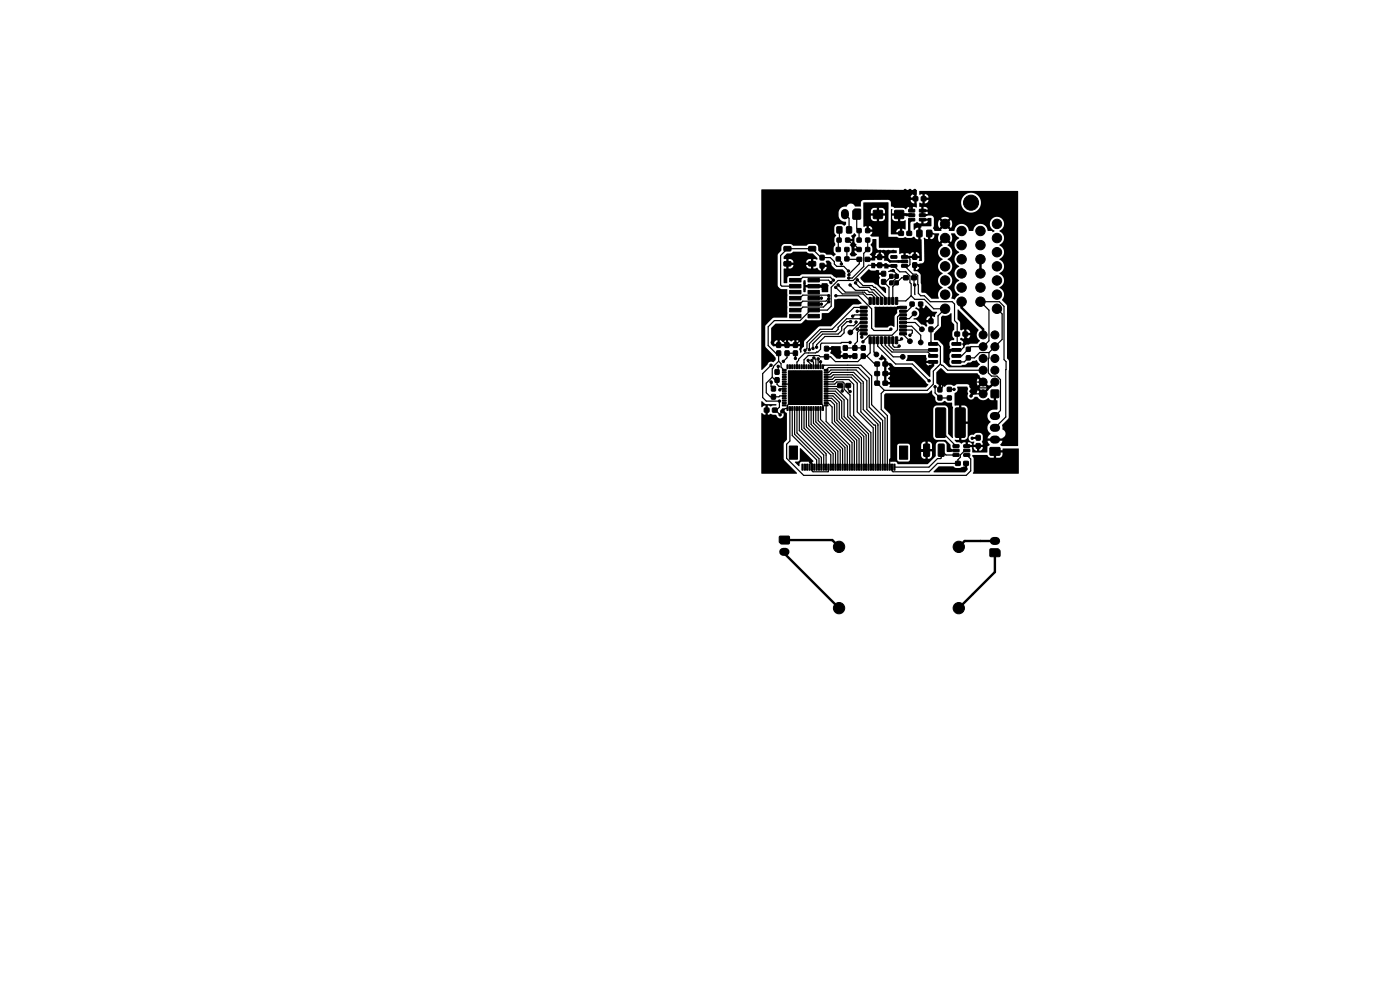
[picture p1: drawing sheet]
<svg xmlns="http://www.w3.org/2000/svg" width="297mm" height="210mm" viewBox="0 0 297 210" stroke-linecap="round" stroke-linejoin="round" font-family="sans-serif">
<g fill="#000" stroke="#000" stroke-width=".21">
<path d="M166.3 55.5h1.4l.1 .2v.6l-.2 .2-1.2-.1-.1-.2zM166.3 52.3h1.4l.1 .2v.6l-.2 .2-1.2-.1-.1-.2zM167.5 59.1h2.4v.7h-2.4zM171.6 55.5h1.3l.2 .2v.6l-.3 .2-1.1-.1-.2-.2zM171.6 52.3h1.3l.2 .2v.6l-.3 .2-1.1-.1-.2-.2zM171.4 59.1h2.4v.7h-2.4zM174 55.9h.8v.9h-.8zM174 54.2h.8v.9h-.8zM177.4 52.5h.9v.8h-.9zM177.6 48.1h1v1.3h-1zM177.6 50.5h.8v.8h-.8zM177.4 54.5h.9v.8h-.9z"/>
<path d="M179.2 52.5h.9v.8h-.9zM179.4 50.5h.8v.8h-.8zM179.6 48.1h1v1.3h-1zM179.2 54.5h.9v.8h-.9zM181.8 50.5h.9v.8h-.9zM181.8 54.6h1v.8h-1zM181 44.7l.4-.4 1.1 .1v2.1h-1.5zM181.8 52.5h.9v.8h-.9zM181.8 48.5h.9v.8h-.9zM183.6 54.6h.9v.8h-.9zM183.7 50.5h.8v.8h-.8zM183.7 52.5h.8v.8h-.8z"/>
<path d="M183.7 48.5h.8v.8h-.8zM186.2 54.1h.8v.9h-.8zM186.2 55.8h.8v.9h-.8zM187 57.6h.9v.9h-.9zM185.3 44.7h1.9v1.6h-1.9zM188.8 58.2h.6v.8h-.6zM188.8 59.6h.6v.8h-.6zM189 54.3l1.2-.1 .1 .5-1.2 .1zM189 56.2l1.2-.1 .1 .5-1.2 .1zM189.9 59.6h.6v.8h-.6zM189.9 58.2h.6v.8h-.6zM190.7 49.1h.9v.8h-.9z"/>
<path d="M191.7 58.5h.9v.8h-.9zM189.8 44.7h1.9v1.6h-1.9zM192.4 49.1h1v.8h-1zM191.3 56.2l1.2-.1 .1 .5-1.3 .1zM191.3 55.2h1.2l.1 .5h-1.3zM191.3 54.3l1.2-.1 .1 .5-1.3 .1zM193.4 58.5h1v.8h-1zM193.7 41.8h1v.8h-1zM193.7 55.8h.8v.9h-.8zM193.7 54h.8v1h-.8zM192.8 44.4h1.2l.1 .5-1.3 .1zM192.8 45.4l1.2-.1 .1 .5-1.3 .1z"/>
<path d="M192.8 46.3h1.2l.1 .5-1.3 .1zM195.5 41.8h.9v.8h-.9zM194.5 48.9h1.1v1.3h-1.1zM195.1 46.3h1.2v.5l-1.2 .1zM195.1 45.4l1.2-.1v.5l-1.2 .1zM195.1 44.4h1.2v.5l-1.2 .1zM196.6 48.9h1v1.3h-1zM164.4 78.4h.9v1h-.9zM164.8 74.5h.8v.9h-.8zM164.8 72.7h.8v1h-.8zM166.6 74.5h.8v.9h-.8zM166.6 72.7h.8v1h-.8z"/>
<path d="M166 78.4h.8v.2h-.8zM166 78.9h.8v.2h-.8zM166 79.4h.8v.2h-.8zM166 79.9h.8v.2h-.8zM167 77.4h.2v.8h-.3zM167.2 78.7h7.2v7.1h-7.2zM167.5 77.4h.2v.8h-.3zM168 77.4h.2v.8h-.3zM168.3 74.5h.8v.9h-.8zM168.3 72.7h.8v1h-.8zM168.5 77.4h.2v.8h-.3zM169 77.4h.2v.8h-.3z"/>
<path d="M169.5 77.4h.2v.8h-.3zM167.5 66.7h2.4v.7h-2.4zM167.5 65.4h2.4v.8h-2.4zM167.5 64.1h2.4v.8h-2.4zM167.5 62.9h2.4v.7h-2.4zM167.5 61.6h2.4v.7h-2.4zM167.5 60.3h2.4v.8h-2.4zM170 77.4h.2v.8h-.3zM170.5 77.4h.2v.8h-.3zM171 77.4h.2v.8h-.3zM171.5 77.4h.2v.8h-.3zM172 77.4h.2v.8h-.3z"/>
<path d="M172.5 77.4h.2v.8h-.3zM173 77.4h.2v.8h-.3zM173.5 77.4h.2v.8h-.3zM171.4 66.7h2.4v.7h-2.4zM171.4 65.4h2.4v.8h-2.4zM171.4 64.1h2.4v.8h-2.4zM171.4 62.9h2.4v.7h-2.4zM171.4 61.6h2.4v.7h-2.4zM171.4 60.3h2.4v.8h-2.4zM174 77.4h.2v.8h-.3zM174.5 77.4h.2v.8h-.3zM174.9 75.2h.9v1h-.9z"/>
<path d="M174.9 73.5h.9v.9h-.9zM174.9 79.9h.7l.1 .2h-.8zM174.9 79.4h.7l.1 .2h-.8zM174.9 78.9h.7l.1 .2h-.8zM174.9 78.4h.7l.1 .2h-.8zM178.9 73.3h.8v1h-.8zM178.9 75.1h.8v.9h-.8zM181 73.3h.8v1h-.8zM181 75.1h.8v.9h-.8zM182.7 75.1h.8v.9h-.8zM182.7 73.3h.8v1h-.8zM182.5 65h1.4l.1 .4h-1.4z"/>
<path d="M182.5 65.8h1.4l.1 .4h-1.4zM182.5 66.6h1.4l.1 .4h-1.4zM182.5 67.4h1.4l.1 .4h-1.4zM182.5 68.2h1.4l.1 .4h-1.4zM182.5 69h1.4l.1 .4h-1.4zM182.5 69.8h1.4l.1 .4h-1.4zM182.5 70.6h1.4l.1 .4h-1.4zM184.4 63.1l.4 .1v1.4l-.4-.1zM184.4 71.5h.4v1.4h-.4zM185.2 63.1l.4 .1v1.4l-.4-.1zM185.2 71.5h.4v1.4h-.4zM186 63.1l.4 .1v1.4l-.4-.1z"/>
<path d="M186 71.5h.4v1.4h-.4zM185.6 78.8h.9v.9h-.9zM185.6 76.8h.9v.8h-.9zM186.8 63.1l.4 .1v1.4l-.4-.1zM186.8 71.5h.4v1.4h-.4zM187 59.3h.9v1h-.9zM187.6 63.1l.4 .1v1.4l-.4-.1zM187.6 71.5h.4v1.4h-.4zM187.3 78.8h1v.9h-1zM187.3 76.8h1v.8h-1zM188.4 63.1l.4 .1v1.4l-.4-.1zM188.4 71.5h.4v1.4h-.4z"/>
<path d="M189.2 63.1l.4 .1v1.4l-.4-.1zM189.2 71.5h.4v1.4h-.4zM190 63.1l.4 .1v1.4l-.4-.1zM190 71.5h.4v1.4h-.4zM190.9 70.6h1.3l.1 .4h-1.4zM190.9 69.8h1.3l.1 .4h-1.4zM190.9 69h1.3l.1 .4h-1.4zM190.9 68.2h1.3l.1 .4h-1.4zM190.9 67.4h1.3l.1 .4h-1.4zM190.9 66.6h1.3l.1 .4h-1.4zM190.9 65.8h1.3l.1 .4h-1.4zM190.9 65h1.3l.1 .4h-1.4z"/>
<path d="M193.1 64.1h.8v.8h-.8zM194.9 64.1h.8v.8h-.8zM197 72.7h1.8l.1 .5h-1.8zM197 74l1.8-.1 .1 .5-1.8 .1zM197 75.2h1.8l.1 .5-1.8 .1zM197 76.5h1.8l.1 .5-1.8 .1zM197.1 69.4h.8v.9h-.8zM197.1 67.7h.8v.9h-.8zM202 76.5h1.8l.1 .5-1.9 .1zM202 75.2h1.8l.1 .5-1.9 .1zM202 74l1.8-.1 .1 .5-1.9 .1zM202 72.7h1.8l.1 .5h-1.9z"/>
<path d="M202.6 70.5h.9v.8h-.9zM204.3 70.5h1v.8h-1zM205 73.7h.8v.8h-.8zM205 75.5h.8v.8h-.8zM162.2 86.6h.9v.8h-.9zM163.7 83.7h.8v.9h-.8zM163.7 82h.8v.9h-.8zM164.4 80.2h.9v.9h-.9zM163.9 86.6h.9v.8h-.9zM166 80.4h.8v.2h-.8zM166 80.9h.8v.2h-.8zM166 81.4h.8v.2h-.8z"/>
<path d="M166 81.9h.8v.2h-.8zM166 82.4h.8v.2h-.8zM166 82.9h.8v.2h-.8zM166 83.4h.8v.2h-.8zM166 83.9h.8v.2h-.8zM166 84.4h.8v.2h-.8zM166 84.9h.8v.2h-.8zM166 85.4h.8v.2h-.8zM166 85.9h.8v.2h-.8zM167 86.3h.2v.8l-.3-.1zM167.5 86.3h.2v.8l-.3-.1zM168 86.3h.2v.8l-.3-.1z"/>
<path d="M168.5 86.3h.2v.8l-.3-.1zM169 86.3h.2v.8l-.3-.1zM167.4 94.6h1.8v2.8h-1.8zM169.5 86.3h.2v.8l-.3-.1zM170 86.3h.2v.8l-.3-.1zM170.1 98.4h.3v1.3h-.3zM170.5 86.3h.2v.8l-.3-.1zM170.6 98.4h.3v1.3h-.3zM171 86.3h.2v.8l-.3-.1zM171.1 98.4h.3v1.3h-.3zM171.5 86.3h.2v.8l-.3-.1zM171.6 98.4h.3v1.3h-.3z"/>
<path d="M172 86.3h.2v.8l-.3-.1zM172.1 98.4h.3v1.3h-.3zM172.5 86.3h.2v.8l-.3-.1zM172.6 98.4h.3v1.3h-.3zM173 86.3h.2v.8l-.3-.1zM173.1 98.4h.3v1.3h-.3zM173.5 86.3h.2v.8l-.3-.1zM173.6 98.4h.3v1.3h-.3zM174 86.3h.2v.8l-.3-.1zM174.1 98.4h.3v1.3h-.3zM174.5 86.3h.2v.8l-.3-.1zM174.6 98.4h.3v1.3h-.3z"/>
<path d="M175.1 98.4h.3v1.3h-.3zM174.9 85.9h.7l.1 .2h-.8zM174.9 85.4h.7l.1 .2h-.8zM174.9 84.9h.7l.1 .2h-.8zM174.9 84.4h.7l.1 .2h-.8zM174.9 83.9h.7l.1 .2h-.8zM174.9 83.4h.7l.1 .2h-.8zM174.9 82.9h.7l.1 .2h-.8zM174.9 82.4h.7l.1 .2h-.8zM174.9 81.9h.7l.1 .2h-.8zM174.9 81.4h.7l.1 .2h-.8zM174.9 80.9h.7l.1 .2h-.8z"/>
<path d="M174.9 80.4h.7l.1 .2h-.8zM175.6 98.4h.3v1.3h-.3zM176.1 98.4h.3v1.3h-.3zM176.6 98.4h.3v1.3h-.3zM177.1 98.4h.3v1.3h-.3zM177.7 81.4h1v.8h-1zM177.6 98.4h.3v1.3h-.3zM178.1 98.4h.3v1.3h-.3zM178.6 98.4h.3v1.3h-.3zM179.1 98.4h.3v1.3h-.3zM179.5 81.4h.9v.8h-.9zM179.6 98.4h.3v1.3h-.3z"/>
<path d="M180.1 98.4h.3v1.3h-.3zM180.6 98.4h.3v1.3h-.3zM181.1 98.4h.3v1.3h-.3zM181.6 98.4h.3v1.3h-.3zM182.1 98.4h.3v1.3h-.3zM182.6 98.4h.3v1.3h-.3zM183.1 98.4h.3v1.3h-.3zM183.6 98.4h.3v1.3h-.3zM184.1 98.4h.3v1.3h-.3zM184.6 98.4h.3v1.3h-.3zM185.1 98.4h.3v1.3h-.3zM185.6 98.4h.3v1.3h-.3z"/>
<path d="M186.1 98.4h.3v1.3h-.3zM185.6 80.9h.9v.8h-.9zM186.6 98.4h.3v1.3h-.3zM187.1 98.4h.3v1.3h-.3zM187.6 98.4h.3v1.3h-.3zM187.3 80.9h1v.8h-1zM188.1 98.4h.3v1.3h-.3zM188.6 98.4h.3v1.3h-.3zM189.1 98.4h.3v1.3h-.3zM189.6 98.4h.3v1.3h-.3zM190.8 94.6h1.8v2.8h-1.8zM196 94.3l1-.1 .2 .1v2.3l-.1 .2h-.9l-.3-.1z"/>
<path d="M198.5 86.6l.3-.1h1.5l.3 .3v5.7l-.2 .3h-1.6l-.3-.2zM199 83.9h.8v.9h-.8zM199 82.2h.8v.9h-.8zM199.1 94.3l1-.1 .2 .1v2.3l-.1 .2h-.9l-.3-.1zM201 82.2h.8v.8h-.8zM201 84h.8v.8h-.8zM202.2 94.4l1.2-.1 .1 .5-1.3 .1zM202.2 95.3h1.2l.1 .5-1.3 .1zM202.2 96.3l1.2-.1 .1 .5-1.3 .1zM202.7 86.6l.3-.1h1.5l.3 .3v5.7l-.3 .3h-1.5l-.4-.2zM202.7 97.9h1v.8h-1zM204.5 97.9h.9v.8h-.9z"/>
<path d="M204.5 96.3l1.2-.1v.5l-1.2 .1zM204.5 95.3h1.2v.5l-1.2 .1zM204.5 94.4l1.2-.1v.5l-1.2 .1zM207.1 94.1h.8v1h-.8zM207.1 92.4h.8v.9h-.8zM210.3 82.8h1.5v1.5h-1.5zM210 95h2.1v1.5h-2.1zM165.4 113.8h2v1.5h-1.8l-.3-.4zM210 116.5h1.8l.4 .4-.1 1.1h-2.1z"/>
<circle cx="172.2" cy="57.4" r=".25"/>
<circle cx="175.8" cy="56.6" r=".25"/>
<circle cx="176.3" cy="59.9" r=".25"/>
<circle cx="176.8" cy="59.4" r=".25"/>
<circle cx="178.5" cy="56" r=".25"/>
<circle cx="180" cy="57.5" r=".25"/>
<circle cx="180.1" cy="59" r=".25"/>
<circle cx="180.1" cy="58.3" r=".25"/>
<circle cx="181" cy="52" r=".25"/>
<circle cx="181.5" cy="60" r=".25"/>
<circle cx="181.9" cy="59.4" r=".25"/>
<circle cx="185.2" cy="54.9" r=".25"/>
<circle cx="185.4" cy="53.8" r=".25"/>
<circle cx="185.9" cy="58.4" r=".25"/>
<circle cx="185.9" cy="53.3" r=".25"/>
<circle cx="186.7" cy="53.3" r=".25"/>
<circle cx="187.5" cy="53.3" r=".25"/>
<circle cx="188" cy="54.6" r=".25"/>
<circle cx="188" cy="53.8" r=".25"/>
<circle cx="188.5" cy="53.3" r=".25"/>
<circle cx="189.5" cy="53.3" r=".25"/>
<circle cx="189.5" cy="57.4" r=".25"/>
<circle cx="191" cy="42.2" r=".25"/>
<circle cx="191" cy="41.1" r=".25"/>
<circle cx="192" cy="42.2" r=".25"/>
<circle cx="192" cy="41.1" r=".25"/>
<circle cx="192" cy="40.4" r=".25"/>
<circle cx="193" cy="43.7" r=".25"/>
<circle cx="193" cy="40.4" r=".25"/>
<circle cx="193" cy="41.1" r=".25"/>
<circle cx="193" cy="42.2" r=".25"/>
<circle cx="194.1" cy="41.1" r=".25"/>
<circle cx="194.1" cy="40.4" r=".25"/>
<circle cx="195.1" cy="56.4" r=".25"/>
<circle cx="195.1" cy="57.4" r=".25"/>
<circle cx="196.1" cy="58.4" r=".25"/>
<circle cx="196.1" cy="56.4" r=".25"/>
<circle cx="196.1" cy="57.4" r=".25"/>
<circle cx="196.6" cy="52.6" r=".25"/>
<circle cx="196.6" cy="51.1" r=".25"/>
<circle cx="196.6" cy="51.8" r=".25"/>
<circle cx="197.1" cy="56.4" r=".25"/>
<circle cx="197.1" cy="57.4" r=".25"/>
<circle cx="197.1" cy="58.4" r=".25"/>
<circle cx="197.4" cy="51.8" r=".25"/>
<circle cx="197.4" cy="52.6" r=".25"/>
<circle cx="197.4" cy="51.1" r=".25"/>
<circle cx="198.1" cy="52.6" r=".25"/>
<circle cx="198.1" cy="56.4" r=".25"/>
<circle cx="198.1" cy="58.4" r=".25"/>
<circle cx="198.1" cy="51.8" r=".25"/>
<circle cx="198.1" cy="51.1" r=".25"/>
<circle cx="198.1" cy="57.4" r=".25"/>
<circle cx="199.4" cy="51.8" r=".25"/>
<circle cx="200.5" cy="53.5" r="1"/>
<circle cx="200.5" cy="59.5" r="1"/>
<circle cx="200.5" cy="50.5" r="1"/>
<circle cx="200.5" cy="56.5" r="1"/>
<circle cx="200.5" cy="47.5" r="1"/>
<circle cx="204" cy="55" r="1"/>
<circle cx="204" cy="49" r="1"/>
<circle cx="204" cy="52" r="1"/>
<circle cx="204" cy="58" r="1"/>
<circle cx="206" cy="43" r="1.6"/>
<circle cx="208" cy="49" r="1"/>
<circle cx="208" cy="55" r="1"/>
<circle cx="208" cy="52" r="1"/>
<circle cx="208" cy="58" r="1"/>
<circle cx="211.5" cy="59.5" r="1"/>
<circle cx="211.5" cy="53.5" r="1"/>
<circle cx="211.5" cy="50.5" r="1"/>
<circle cx="211.5" cy="56.5" r="1"/>
<circle cx="211.5" cy="47.5" r="1"/>
<circle cx="163.6" cy="77.5" r=".25"/>
<circle cx="163.8" cy="72.6" r=".25"/>
<circle cx="165.1" cy="77.7" r=".25"/>
<circle cx="166.1" cy="72.1" r=".25"/>
<circle cx="166.2" cy="76.7" r=".25"/>
<circle cx="168.7" cy="76" r=".25"/>
<circle cx="169.7" cy="71.9" r=".25"/>
<circle cx="170.8" cy="74.3" r=".25"/>
<circle cx="171.4" cy="76.5" r=".25"/>
<circle cx="171.7" cy="74.2" r=".25"/>
<circle cx="172.2" cy="76.5" r=".25"/>
<circle cx="172.5" cy="73.9" r=".25"/>
<circle cx="172.7" cy="75.9" r=".25"/>
<circle cx="173.2" cy="73.7" r=".25"/>
<circle cx="173.6" cy="76.1" r=".25"/>
<circle cx="174.1" cy="76.7" r=".25"/>
<circle cx="174.2" cy="64.5" r=".25"/>
<circle cx="174.2" cy="60.7" r=".25"/>
<circle cx="174.2" cy="63.2" r=".25"/>
<circle cx="175.8" cy="64" r=".25"/>
<circle cx="175.8" cy="63.4" r=".25"/>
<circle cx="175.8" cy="62.7" r=".25"/>
<circle cx="176.6" cy="73.8" r=".25"/>
<circle cx="177.3" cy="61" r=".25"/>
<circle cx="177.3" cy="62.7" r=".25"/>
<circle cx="177.8" cy="60.5" r=".25"/>
<circle cx="178.1" cy="75.7" r=".25"/>
<circle cx="180.3" cy="75.7" r=".25"/>
<circle cx="180.3" cy="72.6" r=".25"/>
<circle cx="180.3" cy="60.5" r=".25"/>
<circle cx="180.4" cy="70.5" r=".5"/>
<circle cx="180.4" cy="68.2" r=".25"/>
<circle cx="180.9" cy="67.1" r=".25"/>
<circle cx="181.6" cy="68.3" r=".25"/>
<circle cx="181.9" cy="69.8" r=".25"/>
<circle cx="181.9" cy="66" r=".25"/>
<circle cx="182.8" cy="71.5" r=".25"/>
<circle cx="183.1" cy="72.5" r=".25"/>
<circle cx="185.9" cy="75.2" r=".5"/>
<circle cx="189" cy="79.2" r=".25"/>
<circle cx="189" cy="77.5" r=".25"/>
<circle cx="189" cy="69.8" r=".25"/>
<circle cx="190.5" cy="65.3" r=".25"/>
<circle cx="190.8" cy="73.4" r=".25"/>
<circle cx="191.3" cy="71.9" r=".25"/>
<circle cx="191.5" cy="75.7" r=".5"/>
<circle cx="193" cy="72.4" r=".5"/>
<circle cx="193" cy="71.1" r=".25"/>
<circle cx="194" cy="66.5" r=".5"/>
<circle cx="194.1" cy="60.5" r=".25"/>
<circle cx="195.3" cy="72.6" r=".5"/>
<circle cx="195.5" cy="65.5" r=".25"/>
<circle cx="195.6" cy="69.9" r=".5"/>
<circle cx="197.4" cy="77.7" r=".25"/>
<circle cx="200.5" cy="62.5" r="1"/>
<circle cx="200.5" cy="65.5" r="1"/>
<circle cx="201.5" cy="74.5" r=".25"/>
<circle cx="204" cy="61" r="1"/>
<circle cx="204" cy="64" r="1"/>
<circle cx="204.5" cy="73" r=".25"/>
<circle cx="205" cy="71.9" r=".25"/>
<circle cx="208" cy="61" r="1"/>
<circle cx="208" cy="64" r="1"/>
<circle cx="208.6" cy="76" r=".85"/>
<circle cx="208.6" cy="73.5" r=".85"/>
<circle cx="208.6" cy="78.5" r=".85"/>
<circle cx="208.6" cy="71" r=".85"/>
<circle cx="211.1" cy="76" r=".85"/>
<circle cx="211.1" cy="73.5" r=".85"/>
<circle cx="211.1" cy="78.5" r=".85"/>
<circle cx="211.1" cy="71" r=".85"/>
<circle cx="211.5" cy="62.5" r="1"/>
<circle cx="211.5" cy="65.5" r="1"/>
<circle cx="163.6" cy="81" r=".25"/>
<circle cx="165.4" cy="85.1" r=".25"/>
<circle cx="165.4" cy="82.7" r=".25"/>
<circle cx="165.5" cy="88" r=".25"/>
<circle cx="165.9" cy="87.4" r=".25"/>
<circle cx="172" cy="98" r=".25"/>
<circle cx="178.7" cy="83" r=".25"/>
<circle cx="180.3" cy="83.1" r=".25"/>
<circle cx="189" cy="97.5" r=".25"/>
<circle cx="189" cy="81.3" r=".25"/>
<circle cx="194.6" cy="95.8" r=".25"/>
<circle cx="197.1" cy="80.8" r=".25"/>
<circle cx="198.4" cy="82" r=".25"/>
<circle cx="200" cy="81.5" r=".25"/>
<circle cx="201.7" cy="95.5" r=".25"/>
<circle cx="202.4" cy="82.6" r=".25"/>
<circle cx="204.5" cy="99.3" r=".25"/>
<circle cx="206" cy="82" r=".25"/>
<circle cx="206" cy="83" r=".25"/>
<circle cx="206" cy="84" r=".25"/>
<circle cx="206.2" cy="93" r=".25"/>
<circle cx="208.6" cy="81" r=".85"/>
<circle cx="208.6" cy="83.5" r=".85"/>
<circle cx="211" cy="98.5" r=".25"/>
<circle cx="211.1" cy="81" r=".85"/>
<circle cx="178" cy="116" r="1.2"/>
<circle cx="203.4" cy="116" r="1.2"/>
<circle cx="178" cy="129" r="1.2"/>
<circle cx="203.4" cy="129" r="1.2"/>
</g>
<path d="M179.2 45.2v.5M210.8 93.3h.5M210.8 90.8h.5M210.8 88.3h.5M166.1 117.1h.5M210.8 114.8h.5" fill="none" stroke="#000" stroke-width="1.7"/>
<g fill="none" stroke="#000" stroke-width=".25">
<path d="M168.7 59.4h1l.6-.6h5.9l.6 .6M172.3 56l-.1 1.4M172.6 59.4h3.2l.5 .5M174.4 56.4h1.1l.3 .2M177.8 54.9l.7 .7v.4M178.1 48.8v2.1l-.3 .2v1.8M179 56.5h-1.5l-.5-.5v-.5l-.9-.9h-1.9l-1.9-1.8h-5.3l-1.4 1.4v6.3l.3 .2h2.8M179 56.5h.1M179 56.5l1 1M179.2 45.4l.9 .9v2.5M179.7 52.9l.1 2.1h2.5v1l-2.2 2.3M179.9 50.9l1.1 1.1h.3l.9 .9"/>
<path d="M181.7 45.4v3l.5 .5v2M181.9 59.4l1.2 1.2h1.9l.4 .4h.3l2.1 2.1v.7M184.1 52.9l-.9 .8v2.8l-2.4 2.5h-.7M184.1 50.9v2h-.2M185.2 54.9l-.2 .1h-1M186.3 45.5v.7M186.6 56.3l.2 .1M187.8 58.1h-1.5l-.4 .3M189.1 58.6l-1.2 1.2h-.4l1.1 1.1v2.9M189.5 57.4l.7 .7v.8l-1.1 1.1M192 54.4l-.1 .1h.7l.4 .5v1.1l-.2 .3h-.9l1.8 1.8h.7l.3 .3 .1 3.7 .5 .5h.8l1.2 1.3h4.7l.5 .5v3.5l.6 .6v4.2l-.2 .2M192.2 58.9h-.9l-1.9 1.9v3"/>
<path d="M193 43.7v.6l.4 .4M193.9 58.9v1.4l.2 .2M200.5 50.5h.1M200.5 50.5v.2l-1.1 1.1M163.6 77.5l-1.8 1.7v5.1l.8 .8h2.8v1.3l-.7 .6h-.3M163.8 72.6l.6 .6h.8M165.1 77.7v.9l-.3 .3M165.2 76.6l.5 .5v.8l.6 .6M165.2 76.6l-1.1 1.1v.3l-.3 .2v1.8M166.1 72.1v.3l.9 .8M168.7 76v-1.1h-1.7v1l-.8 .8M169.7 71.9v.4l-1 .9"/>
<path d="M171.4 76.5v.2l.7 .6v.5M172.2 76.5l.4 .3v1M172.6 60.7h1.6M172.6 63.2h1.6M172.6 64.5h1.6M172.7 75.9l.4 .4v1.5M173.6 76.1v1.7M174.1 76.7v1.1M174.1 77.8h.1M174.6 77.8l.3-.3h7.7l2.3 2.3v6.1l2.8 2.8v10.4M175.3 78.5l.5-.5h6.3l2.3 2.3v6.1l2.9 2.8v9.9M175.3 79.5h.7l.5-.5h4.6l2 2v5.9l3.2 3.1v9.1"/>
<path d="M175.3 80h1l.5-.5h4l1.8 1.8v6.1l2.8 2.8h.3v8.9M175.3 79h.5l.5-.5h5.3l2.3 2.3v6.1l2.9 2.8v9.4M175.8 62.7l-.1-.1h-5.4l-.6 .6h-1M175.8 63.4l-.6 .5h-4.9l-.6 .6h-1M175.8 64l-1.1 1.1h-4.4l-.6 .7h-1M176.6 73.8h-1.1l-.2 .2M177.3 61l1.4 1.4h4.4l1.5 1.4M177.4 62.7h4.7l2.8 2.8v4.1l.5 .5h3.3l.3-.3M177.8 60.5l1.5 1.5h4.1l.5 .5h1l.5 .5v.8M179.3 75.5h-1.1l-.1 .2M180.3 60.5l1.2 1.1h2.5l.4 .4h.7l1.1 1.1v.7M180.3 72.6l-6 .2-.2 .2v1.1l-.6 .6-.5 .2h-2.2l-1.4 1.3v.3l-.3 .3v1"/>
<path d="M180.4 68.2h-.7l-1.1 1.1v.8l-.8 .8h-3.3l-2 2v1M181.4 75.5h-.9l-.2 .2M181.5 60l.9 1h2l.5 .5h.5l1.6 1.6v.7M181.6 68.3v.3l-.5 .5h-1.3l-.7 .8v.7l-.8 .8h-3.3l-1.8 1.8v.5M183.1 73.8h-3.8M183.2 70.8l-.4 .4v.3M183.2 69.2h-.7l-.6 .6M183.2 65.2h-2l-4.7 4.7h-2.5l-2.8 2.7v1.3l-.4 .4M183.2 66h-1.3M183.2 70h-.8l-.5 .5v1.9l-.5 .6v.8M183.2 66.8h-2l-.2 .3M183.2 67.6h-3.6l-1.8 1.8v.5l-.5 .5h-3.1l-2.5 2.5v1.3"/>
<path d="M183.2 68.4h-.7l-2.1 2.1M183.9 75.6l1.7 1.6h.5v4.1l1.5 1.5M183.9 75.6h-.8l-1.1 1.1h-4.8l-1-1h-2.2l-.3-.3h-2.2l-.9 .9v1.5M184.1 71.4h.1M184.3 71.2h.1M184.6 72.2v2.6l-.7 .8M185.4 72.2v2.5l.5 .5M186.2 72.2v1.2l3.8 3.8h3.5l3.6 3.6M187 72.2v1l2.5 2.5h2M187.8 72.2v1l1.4 1.5h7.6l.9 .8h.3M187.8 79.2h1.2M187.8 77.2h.9l.3 .3"/>
<path d="M188.6 72.2v1.1l.9 .9h8.5M189.4 72.2v1.1l.3 .4h.8l.3-.3M191.3 71.9l-.3 .3h-.8M191.6 65.2l-1.1 .1M191.6 69.2h1.8l1.9 1.9v1.5M191.6 70h1.9v.6l-.5 .5M191.6 66.8h-.8l-.4 .4v2.7l-1.2 1.2h-4.8l-1.3 1.3M191.6 70.8l1.4 1.6M191.6 68.4h2.5l1.5 1.5M192.5 63.5l-.3 .3h-2M192.5 63.5h.1M193.3 62.7v-2.5l-.3-.3v-1.4l-.9-.8h-1.2l-1.3-1.3h-.6l-.1-.1h-4.7l-3.2 3.2h-3.2l-1.5 1.4v4.1l-.8 .8h-3.5l-2.3 2.2h-5.4l-1.3 1.3v4l1.6 1.6h.6v1.7"/>
<path d="M193.3 62.7l-.8 .8M193.3 62.7l.8 .8h2l2 2h2.4l-1.5 1.5v2l-.9 .9h-.6v2.6l.5 .5h.9l.6 .5v3.7M193.5 64.5v.5l-1 1h-.9M194 66.5l-1.1 1.1h-1.3M195.3 64.5l.2 .2v.8M198 76.8v.3l-.6 .6M199.5 77.2l-1.5 1.5v2.8l-1.3 1.3h-9.1M199.5 77.2l.3 .3h.2l1 1h7.6M202.9 75.5h1.1l2-2h2.6l1.2-1.2v-6.5l-1.8-1.8h4l1 1v11.3l.4 .4v11.8l-2.3 2.3M202.9 74.2h-1.1l-.3 .3M204.5 73v.6l-.6 .6M204.8 70.9v.8l.2 .2"/>
<path d="M208 78l.6 .5M208.6 78.5l-.3 .3M209.8 74.8l-.1 4.3 .6 .7h1.2l.7 .7v6.6l-1.1 1.2M209.8 74.8h-2l-1.1 1.1h-1.3l-.8 .9h-1.7M211.5 65.5l1.1 1.1v5.4l-2.8 2.8M163.6 81v.9l.5 .5M163.8 80l-1.2 1.3v2l.8 .9h1.9l.2-.2h.9M163.8 80l.6 .6M164.5 87l1 1M164.8 80.6v.9l.5 .5h1.1M166.4 81.5h3.7l4.5 4.5v.7M166.4 82.5h-.7l-.3 .2"/>
<path d="M167.6 86.7v6.8l-.7 .7v3l3.6 3.6h34.5l.9-.9v-2.5l-.8-.9M168.1 86.7v5.7l5.2 5.2v1.5M168.6 86.7v5.4l5.2 5.2v1.8M169.1 86.7v5.2l5.1 5.1v2.1M169.6 86.7v4.6l5.2 5.2-.1 2.6M170.1 86.7v4.4l5.1 5.2v2.8M170.6 86.7v4.1l5.7 5.7v2.6M170.8 82.2l-3.7 3.8v.7h-.5l-.7 .7M171.1 86.7v3.9l5.7 5.6v2.9M171.6 86.7v3.6l5.6 5.7v3.1M172 98l.2 .3v1.6l.3 .2h3.2v-1M172.1 86.7v3.3l5.6 5.7v3.4"/>
<path d="M172.6 86.7v3.1l5.6 5.6v3.7M173.1 86.7v2.8l5.6 5.7v3.9M173.6 86.7v2.5l5.6 5.7v4.2M174.1 86.7v2.3l5.7 5.7v4.4M175.3 81.5h1.8l.4-.5h1.3l.3 .3v1.3l1.2 1.2v4.3l3.9 3.9v7.1M175.3 85h.9l.8 .9v3.5l4.2 4.2v5.5M175.3 84.5h1.1l1.1 1.1v3.6l4.2 4.2v5.7M175.3 84h1.4l1.4 1.3v3.6l4.1 4.2v6M175.3 83h1.9l1.9 1.8v3.6l4.2 4.2v6.5M175.3 82h2.7l.2-.2 .5 .4v.8M175.3 82.5h2.2l2.3 2.3v3.6l4 3.9v6.8M175.3 85.5h.4l.8 .8v3.4l4.2 4.2v5.2"/>
<path d="M175.3 81h1.5l.5-.5h2.8l1 1v6.6l3.6 3.7v7.3M175.3 86v3.4l5 5v4.7M175.3 80.5h1.3l.4-.5h3.6l1.3 1.3v6.1l3.3 3.4v8.3M175.3 83.5h1.6l1.7 1.6v3.5l4.2 4.2v6.3M179.9 81.8v.9l.4 .4M187.6 82.8l-.7 .7v3.4l1.3 1.3v10.9M187.8 81.3h1.2M189 97.5l-.3 .3v1.3M196.6 95.5l-.3 .3h-1.7M198.4 82v1.4l1 1M199.4 84.4h2M199.6 89.7v1.7l3.2 3.2"/>
<path d="M200 81.5v.5l-.6 .6M201.4 82.6h1M201.7 95.5l1.1 .1M202.8 96.5h-2.1l-1-1v1.6l-.2 .2h-.6l-1.8 1.8h-7.3M204.9 98.3v.5l-.4 .5M205.1 95.6h-.4l-1 .9v.5l-.5 .5v.8h-4.3l-1.8 1.8h-7.7l-.2-.2v-.8M207.5 92.9l-1.3 .1M208.6 81h-1.9l-.7 .8M208.6 83.5h-2.3l-.3 .3M211.1 81l-1.3 1.3h-3.1l-.7 .7M211.1 95.8v2.6"/>
</g>
<path d="M188 54.6l.8 .9h3.1M190.7 45.5h2.6l.1 .1M193.4 46.6l-.5 .5v2.4M208 55v3M204 64v1.3l4.6 4.5v1.2M166.4 114.6h10.2l1.4 1.4M166.4 117.1v.3l11.6 11.6M211.1 117.3v4l-7.7 7.7M211.1 114.8h-6.4l-1.3 1.2" fill="none" stroke="#000" stroke-width=".51"/>
<g fill="#000">
<path d="M170.5 59.5h.4v1h3.4l.1-.4h1.1l.3 .5-.1 1.3-1.3 .1-.1-1h-3.4v.9l-.4 .1zM166.3 54.4l.7-.6 .7-.1 .6-.3h2.8l.5 .3 .8 .1 1 1v.3l-.9-.1v2l.5-.1a.32 .32 0 0 1 .4-.1 .32 .32 0 0 1 .2 .3l.4 .3h.7a.73 .73 0 0 0 .7-.8h-.7v.8h-.5v-1h.2l.1-.3h.9l-.2-.7 .1-.1h.5l.5 .4 .1 .6 .7 .7 .3 .1 1.4 .1 .4 .4 .2 .4-.1 .8-1.9 .2-1.2-.8h-6l-.6 .4h-2.3l-.3 .4v1l-.6 .1-.2-.1v-2.9l.2-.2a1.7 1.7 0 0 0 1.9-.4v-.2h2.7a.8 .8 0 0 0 1 .7v-.8h-4.7v.8h-.5v-1.3h5.2v-.7a.8 .8 0 0 0-1 .7h-2.7a.8 .8 0 0 0-1-.7v.7h-.5v-.7l-.5-.1zM161.5 40.2h17.7l15.3 .2v3.6l-.8-.1-.1 .8-.4-.1v-.7h-.6l-.4 .5-.5-.3h-1.9l-.7-.3-.1-.9-.4-.4h4.6l.2 .5 .6 .1v-.7h-10.7l-.6 .3-.1 1.1h-1.2a1.04 1.04 0 0 0-.9-.6 1.04 1.04 0 0 0-1 .6h-.1a1.35 1.35 0 0 0-1.5 1.3v.9a1.35 1.35 0 0 0 1.5 1l.1 .6-.3 .3-.6-.3h-.9l-.6 .4-.1 1.4 .4 .6-.4 .5 .2 1.5-.3 .5-.1 .7 .5 .7-.4 .5-.6-.4h-.9l-.6-.4h-.8l-.4-.5-.1-.9-.5-.4h-1.4l-.5 .3h-2.8l-.6-.3h-1.2a.74 .74 0 0 0-.7 .7v.6l-.8 1v6.4l.6 .8 1.4 .1v5.9l-.1 .1h-2.8l-1.7 1.7v4.4l2.1 2.4v.5l-.5 .4a.78 .78 0 0 0-1.2 .5l-1.1 1.1h-.2v-36.5h32.5v-.7l-.6 .1-.2 .6h-31.7zM180.6 50l.6-.5 .4 .3-.3 .7 .1 1.1a.3 .3 0 0 1 .3 .3 .3 .3 0 0 1-.3 .3l-.1 .5h.9v.4l-.9 .1 .1 .4 .4 .4-.4 .4h-.8l-.3-.5 .3-.6v-.8l-.3-.5 .4-.4 .1-.4h-.9l-.1-.4 .1-.1h.9zM182.5 58.8l1.8-1.7 .6 .3 1.4-.1a.29 .29 0 0 1 .3 .2 .29 .29 0 0 1-.1 .3h.8l.2 .1-.1 .4h-.9v.2a.65 .65 0 0 1 0 .9v.7a.8 .8 0 0 0 1.1 .7l.4 .4-.1 1-1.8-1.7-.8-.5-2-.1-.7-.7zM184.8 55.8h.7l.2 .2h1.9l.1-.2h.4l.5 .4h1v.3l-.1 .1-1 .1-.1 .3-.8-.1v-.4h-1.9l-.1 .4h-.7l-.1-.1zM185.1 50.8h.8v1.8l.3 .4 4 .2v.5h-1.2l-.4 .3-.1 .8 .2 .4 1.5 .1 .5-.2 1.1 .2 .1 .2-1.2 .3-.5-.2h-1.5l-.5-.3h-.6v-.5h-1.9l-.1 .5-1.6-.1 .1-.4h1l-.3-.6 2.8 .1a.73 .73 0 0 0-.7-.8v.8h-.5v-.8a.73 .73 0 0 0-.7 .7h-.9l-.3-.2 .6-.7v-.8l-.4-.6 .3-.4zM183.2 43l5.2-.1 .1 7.3h1.8l.4 .3h.9a.65 .65 0 0 1 .9 0h.8l.6-.3 .3 .4 .6 .2v-2.5l-.4 .1-.4 .4-.2-.2v-1.2l.9-.3a1.6 1.6 0 0 0 1.6 .3l.3-.1 .2-.5h-.9v.6h-.5l.1-.8 .3-.2 1.2-.2 .6 .1v1.6l-2.1 .1v.2l-.2 .1v2.5l.2 .1 .1 4.4-.6 .1v-.6l-3-.2-.3-.2v-.7h.5v.6h2.8a.73 .73 0 0 0-.7-.8v.8h-.5v-.8l-.8 .5a1.62 1.62 0 0 0-1.7-.3l-.5 .1v-1.2h-4.3l-.1-2.4h-1.5l-.3-.3 .3-.3 .2-.4h-1v-.3l-.3-.1v-.1h1.3a.73 .73 0 0 0-.8-.7v.7h-.5v-.7l-.6 .1-.1-1.9h1.6l.2 .4 .4 .3h1.7a.85 .85 0 0 0 .7-1.1h-1.2v1.1h-.5v-1.1h-1.3v.4h-1.6v-1.4h1.6v.5h3a.85 .85 0 0 0-.7-1.2h-.5v1.2h-.5v-1.2l-.8 .1-.5 .6h-1.6zM188.5 57.5l.4-.3h.6l.4 .4-.3 .1h-1.1zM189 44.4h.3l-.1 .9h3.1l1.1 .3-.1 .2-.8 .1-1.5-.1v1.1h.7l.3-.2 .2 .1-.1 1.9-.7-.2v.9l-.2 .1-.1 .2h-2.1v-.5l1.9 .1v-.8a.73 .73 0 0 0-.8 .7h-1.1v-3h.2l.5 .6 .8 .1v-1.1h-1.3v.4h-.2zM196 50.5l.6 .2 .8 .1a.78 .78 0 0 0 .8-1h-.8v1h-.5v-1.1l.3-.4 1.9 .2 .2 .1a1.53 1.53 0 0 0 0 1.8l.6-.6 .3 .3-.6 .6 .4 .3a1.63 1.63 0 0 0-1 1.5 1.63 1.63 0 0 0 1 1.5 1.63 1.63 0 0 0-1 1.5 1.63 1.63 0 0 0 1 1.5 1.63 1.63 0 0 0-1 1.5 1.63 1.63 0 0 0 1 1.5 1.72 1.72 0 0 0-.8 2.3l-1.6 .1-1.2-1.2-.9-.2-.2-3.7-.6-.7-.7-.1-.2-.1 .5-.1a.73 .73 0 0 0 .7-.8h-.7v.8h-.5v-.9l.3-.4 1.5-.1 .4-.5zM201.8 49.6l.7-.1 1 1a1.63 1.63 0 0 0-1 1.5 1.63 1.63 0 0 0 1 1.5 1.63 1.63 0 0 0-1 1.5 1.63 1.63 0 0 0 1 1.5 1.63 1.63 0 0 0-1 1.5 1.63 1.63 0 0 0 1 1.5 1.63 1.63 0 0 0-1 1.5 1.63 1.63 0 0 0 1 1.5l-.6 .5-.3 .5-.7-.1a1.82 1.82 0 0 0-.9-2.4 1.63 1.63 0 0 0 1-1.5 1.63 1.63 0 0 0-1-1.5 1.63 1.63 0 0 0 1-1.5 1.63 1.63 0 0 0-1-1.5 1.63 1.63 0 0 0 1-1.5 1.63 1.63 0 0 0-1-1.5l.4-.3-.6-.6 .3-.3 .6 .6a1.71 1.71 0 0 0 .1-1.8z"/>
<path d="M195 40.6h21v54h-3.6l-.2-.3 .5-.8h-1.1v-.5h1.1a1.07 1.07 0 0 0 .6-1 1.07 1.07 0 0 0-.6-1l-.1-.8 1.3-1.3 .1-.4 .1-11.8-.5-.7v-11.1l-.1-.3-.9-1a1.66 1.66 0 0 0-.6-2.6 1.63 1.63 0 0 0 1-1.5 1.63 1.63 0 0 0-1-1.5 1.63 1.63 0 0 0 1-1.5 1.63 1.63 0 0 0-1-1.5 1.63 1.63 0 0 0 1-1.5 1.63 1.63 0 0 0-1-1.5 1.63 1.63 0 0 0 1-1.5 1.63 1.63 0 0 0-1-1.5 1.52 1.52 0 0 0 .9-2.2 1.52 1.52 0 0 0-2.3-.4 1.52 1.52 0 0 0 .1 2.4l.3 .2-.4 .3-.1-.3h-.9a1.65 1.65 0 0 0-2.6-1.1l-.6 1.1h-.8l-.1-.4a1.51 1.51 0 0 0-1.6-1.1 1.51 1.51 0 0 0-1.4 1.4l-1.2 .1 .1-.3-.6-.6 .3-.3 .6 .6a1.48 1.48 0 0 0 0-1.8l-.6 .6-.3-.3 .5-.7a1.49 1.49 0 0 0-1.7 .1l.6 .6-.3 .3-.7-.5a1.49 1.49 0 0 0 .1 1.7l.6-.6 .3 .3-.6 .6v.3h-1.3l-.4-.5 .2-.6v-1.5l-.3-.6h-2l-.4-.2v-.2h1.4v-.5h-.9v.5h-.5v-1h1.4l-.2-.4-.7-.1v.5h-.5v-.5l-.4-.1v-.8l1.3 .1 .5-.2h7.1v.2a2.11 2.11 0 0 0 3.2 1.7 2.11 2.11 0 0 0 0-3.6 2.11 2.11 0 0 0-3.2 1.7h-7.1l.2-.5h-.8v.7h-.6l.1-1.2h1.3a.73 .73 0 0 0-.8-.7v.7h-.5v-.7l-.7 .1zM167.3 78.7l7 .1v6.9h-7v-4.1l-.2-.1 .2-.1zM175.4 73.8l.9-.1 .1-.3h1.9l.1 .9 .2 .4-.3 .6h2.9l.1 .4-3 .1v.3h-.8l-1.3-1.2 .1-.7h-.9zM164.5 68.7l5.3-.1 1.1-.9 .5 .2h2.7l.2-.4v-1.1l1.5-.1 1-.9 .2-1.9 4.8-.1 1 .8-.1 .2-.5 .2h-1.1l-.3 .1-4.5 4.5h-2.4l-.3 .2-2.9 2.8-.1 1.3a1.17 1.17 0 0 0-.6 1.2l-.2 .1a1.31 1.31 0 0 1-.1-1.3h-5.6l-.5-.6 6.1 .1a.73 .73 0 0 0-.7-.8v.8h-.5v-.8l-.6 .3-.7-.3v.8h-.5v-.8l-.6 .3-.7-.3v.8h-.5v-.8a.73 .73 0 0 0-.7 .7h-.6v-3.3zM187 75.2h.1l.9 .9 .1 .9h.8l.9 .8 3.5 .1 3.6 3.8-.5 .5h-7.7l.1-.7h-.9l-.3-.5h1.2l-.4-.8 .3-.3 .1-.4h-.7v1.5h-.5v-2h1.2l-.4-.8 .3-.3 .1-.4h-.7v1.5h-.5v-2.8l-.6 .2-.6-.2zM185.5 65.1l6-.1v.2l-1.2 .3v.9l-.5 .8-.1 2.2a.93 .93 0 0 0-1.4 .1l-2.7-.1zM193.9 60.6l.3 .1-.1 1.9-.2-.2zM194.2 65.3l.2-.1 .7 .3v-.9l.3-.1 .2 .1v.9a.91 .91 0 0 0 .8-.7l1.4 1.3 1 .1-.4 .5v.5l-.7-.1v.9l-.3 .4h-.9l.2 .6-.2 .3-.4-.3-.6-.2-1.3-1 3 .1v-.8a.73 .73 0 0 0-.7 .7h-2.6l-.1-.2a1.12 1.12 0 0 0 1.2-.9 1.12 1.12 0 0 0-.8-1.3zM192.5 75.3h3.9l.2 .8-.1 .4h1.4l.1 .3h.2v.8l-.8 .9v1.4h-.2l-3-2.9h2.3l.2 .4 .4 .2h.6v-.6h-3.5l-.5-.4h-1.4zM198.7 78.9l.9-.8 1.4 1.1h6.3l1 1.3-.3 .3-.6-.5a1.33 1.33 0 0 0 0 1.5l.6-.5 .3 .3-.5 .6v.2l.5 .6-.3 .3-.6-.5-.2 .8-.7 .2-.5 .4-.2-.2 .1-.5-.1-.5 .1-.5-.1-.4a.71 .71 0 0 0-.7-.6h-2.1a.86 .86 0 0 1-1.3 .1l-1 .2a.31 .31 0 0 1-.3 .3 .31 .31 0 0 1-.3-.3l-.5-.2v1h-.4l-.1-1-.5-.3zM199.7 67.2l.3-.3 .1 .1a1.75 1.75 0 0 0 1.7-.6l.1 1.8 .5 .7v1l-.4 .7 .1 .7 .3 .5v.3a.75 .75 0 0 0-1 .6l.2 .9-.2 .4h1.4l.1 .1-.1 .4h-1.4l.2 .3-.2 .5 .2 .8-.2 .9 .2 .3 .4 .3h1.8l1-.3a1.12 1.12 0 0 1 1.2-.5l.3-.2 .9-.2 .7 .9-.6 .6h-5.9l-1.3-1v-3.7l-.9-.9-1.1-.3v-1.2l1.5-1.6zM203.1 65.7h.2l4.3 4.2a1.65 1.65 0 0 0-.1 2l.4 .4-.5 .6h-1.5l-.4 .2a.91 .91 0 0 0-1 .4l-.2-.1v-.9l-.6-.4v-.3l.2-.2 .4 .2h.7a.73 .73 0 0 0 .8-.7h-.8v.7h-.6l.1-1.2h1.3a.73 .73 0 0 0-.8-.7v.7h-.5v-.7l-.5 .2-.3-.2v-1.5l-.6-.7z"/>
<path d="M161.5 85.1h.2l.7 .6 2.3 .1v.2h-.8a.65 .65 0 0 1-.9 0l-.1 2h.2a.65 .65 0 0 1 .9 0h.6a.85 .85 0 0 0 .8 .7 .85 .85 0 0 0 .9-.6 .95 .95 0 0 0-.7-.9l.4-.6 .4 .1a.83 .83 0 0 0 .5 1v5.5l-.6 1v3.1l.1 .3 2.7 2.8-7.5 .1-.1-12.8 .1-.1 .4 .3 .4 .1v-2l-.9 .4zM163.5 81.2l.2-.2a.2 .2 0 0 1 .2 .2 .2 .2 0 0 1-.2 .2h-.2zM169.7 95.1h.2l2.6 2.6v.2l-.2 .2-.2-.2-2.1 .1-.3 .2-.1 .7h-.2l-.8-.9 .8-.1 .3-.4zM187.6 83.7l.3-.3h8.9l.8-.6 .1 .1 .1 .8 .6 .6a.83 .83 0 0 0 .7 1.1h.7l.7-.4 .5 .4 1 .1v.6l.2 .3-.1 6.5-1-.9v-5.2a.81 .81 0 0 0-.7-.8h-1.8l-.5 .5-.1 6 .2 .5 .4 .3h2l1 1.1 .1 .9 1 .1 .1 .3-1.9 .2-.1-1.5a.74 .74 0 0 0-.7-.7h-.9a.74 .74 0 0 0-.7 .7v2.4l-1.7 1.7h-6.3l-.5-.5-1.1-.1v-3.3h1.4v2.9l.4 .4h2.1l.2-.4 .1-.9h2.3a.76 .76 0 0 0 .9 .7 1.02 1.02 0 0 0 1.4-.6v-.9h-.9v1.5h-.5v-1.5h-.9v.8h-2.3l-.1-2.2h2.4v.9h2.3v-.9a.76 .76 0 0 0-.9-.7v1.6h-.5v-1.6a.76 .76 0 0 0-.9 .7h-2.4l-.3-.3h-1.9l-.3 .2-.2 .3h-1.4v-6.5l-.2-.3-1.1-1.2zM198.1 100l1.1-1.1h3l.6 .4h.9a.65 .65 0 0 1 .9 0l.1-.9 .4-.1 .2 1.3-.6 .6h-6.5zM203 82.1l2.2-.1 .2 .5-.2 .4 .2 .5a.84 .84 0 0 0 .2 1.3 .84 .84 0 0 0 1.2-.5h.6a1.46 1.46 0 0 0 2.3 .2l.4 .4 .7 .1v-.8h.5v.8l.3 .1v1.8l-.1 .1h-.8a1.42 1.42 0 0 0-1.2 1.1 1.42 1.42 0 0 0 .7 1.5 1.48 1.48 0 0 0 0 2.5l-.5 .5-.2 .5h1v.5h-1l.5 .8-.5 .3-.1 1.4h-3.1l-.1-1.1h.3l.5 .7h.8a.73 .73 0 0 0 .7-.8h-.7v.8h-.5v-.8l-1.1 .1-1-.1-.4-.3v-.1h1.4l-.2-.5-.7-.1v.6h-.5v-.6l-.5 .1-.4 .2-.3-.2-.7-.1-.4-.4 .1-.1h2l.6-.4h.3a.85 .85 0 0 0 1.2 .8l-.2 .6h2v-.2a.65 .65 0 0 1 0-.9v-.8l-.4-.5-1-.1-.7 .4a.75 .75 0 0 0-.9 .7h-.3l.1-3h-1.3v3.4h-.5v-3.9h1.8v-2.6l-.2-.5-.3-.2-.8-.1v3.4h-.5v-3.4h-1l.1-2.7a.84 .84 0 0 0 .4-1.2zM206.1 92.8l1.3-.2 .1 .4-1.3 .2-.2-.2zM209.1 81.3l.6 .5h.2l.6-.5 .3 .3-1.7 1.7-.3-.3 .5-.6v-.2l-.5-.6zM206.3 96.6l3.1-.1 .5 .5 .9 .1v-.8h.5v.8h.7a.83 .83 0 0 0 .7-1.1h-1.1v-.5h1.1l.1-.4 3.3 .1v5.3h-9.6l.1-3.2z"/>
</g>
</svg>
